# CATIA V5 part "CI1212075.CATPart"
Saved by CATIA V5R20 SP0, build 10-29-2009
Part number: CI1212075
Bounding box of the stored display mesh (mm): x -12 to 12, y -10.22 to 93, z -13.659 to 13.975
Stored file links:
  C:\Users\Raffaele\Desktop\3D X SITO CF\BOLEX\19-INCLINED ASSEMBLY REF_CI\CI1212075.CATPart

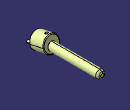
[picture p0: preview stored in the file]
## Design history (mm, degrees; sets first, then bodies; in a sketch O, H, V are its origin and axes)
Set1
  DatumSurface1 to DatumSurface16 "MANIFOLD_SOLID_BREP #379"
  DatumSurface17 to DatumSurface39 "MANIFOLD_SOLID_BREP #1096"
Body1 (main body)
